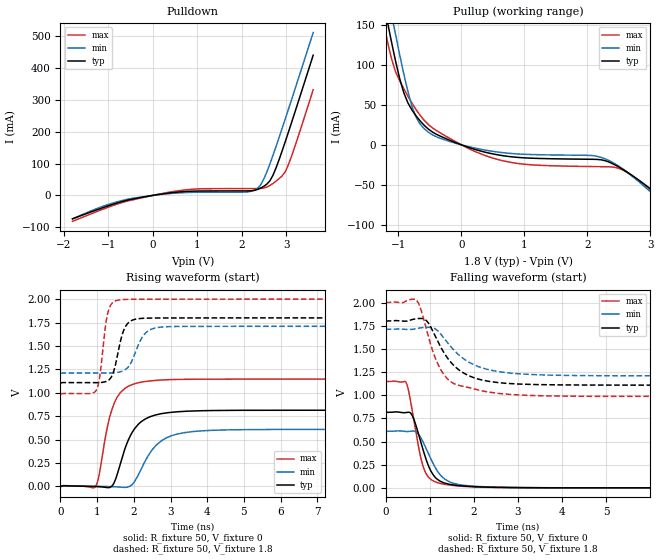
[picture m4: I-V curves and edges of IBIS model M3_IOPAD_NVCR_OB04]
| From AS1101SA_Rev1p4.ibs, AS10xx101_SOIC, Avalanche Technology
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[Model] M3_IOPAD_NVCR_OB04
Model_type Output
Enable   Active-High
Vmeas =  0.9
Cref  =  30e-12
| Capacitance  typ   min   max
C_comp   0   0   0
| Variables   typ   min   max
[GND Clamp Reference]   0   0   0
[POWER Clamp Reference]   1.8   1.71   2
[Pulldown Reference]   0   0   0
[Pullup Reference]   1.8   1.71   2
[Temperature Range]   25   105   -40
[Voltage Range]   1.8   1.71   2
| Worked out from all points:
|   slope of the pulldown table from 0 to 0.27 V, typ, clamps not added: 46.6 ohm
|   slope of the pullup table from 0 to 0.27 V, typ, clamps not added: 38.6 ohm
|   falling waveform, R_fixture 50, V_fixture 0: 20-80 % time 347ps typ, 419ps min, 280ps max; typ from 0.814 V to 0 V
|   falling waveform, R_fixture 50, V_fixture 1.8: 20-80 % time 649ps typ, 769ps min, 500ps max; typ from 1.8 V to 1.1 V
|   rising waveform, R_fixture 50, V_fixture 0: 20-80 % time 520ps typ, 636ps min, 397ps max; typ from 0 V to 0.814 V
|   rising waveform, R_fixture 50, V_fixture 1.8: 20-80 % time 256ps typ, 352ps min, 184ps max; typ from 1.1 V to 1.8 V
[Pulldown]
| Voltage   I(typ)   I(min)   I(max)
-1.8V     -73.53mA   -74.1mA    -81.36mA
-782.1mV  -23.09mA   -19.69mA   -26.48mA
310.3mV   6.56mA     4.883mA    8.631mA
993.1mV   13.72mA    9.848mA    20.32mA
2.076V    14.22mA    10.42mA    21.55mA
2.352V    18.81mA    22.19mA    21.62mA
2.49V     28.4mA     50.7mA     23.2mA
2.628V    45.71mA    98.58mA    31.1mA
2.766V    86.15mA    153.3mA    44.72mA
2.972V    168.6mA    240.1mA    74.33mA
3.179V    257.1mA    329mA      149.7mA
3.6V      441mA      512.1mA    332.5mA
[Pullup]
| Voltage   I(typ)   I(min)   I(max)
-1.8V     421.2mA    457.5mA    393mA
-1.238V   181.2mA    217.5mA    154.6mA
-1.173V   154.7mA    190.5mA    130mA
-1.108V   129.1mA    164mA      108.2mA
-1.043V   104.9mA    138mA      91.61mA
-912.4mV  65.24mA    88.85mA    70.32mA
-716.9mV  36.16mA    34.41mA    44.04mA
-456.2mV  15.91mA    12.39mA    21.19mA
682.8mV   -13.91mA   -10.07mA   -20.42mA
2.214V    -18.73mA   -15.65mA   -27.42mA
2.697V    -37.66mA   -38.46mA   -38.2mA
3.6V      -96.52mA   -101.9mA   -99.3mA
[Ramp]
dV/dt_r   0.488568/0.519945n  0.365787/0.635811n  0.687926/0.397312n
dV/dt_f   0.417076/0.649039n  0.300973/0.768787n  0.608145/0.500349n
R_load = 50
[Falling Waveform]
R_fixture = 50
V_fixture = 0
V_fixture_min = 0
V_fixture_max = 0
| Time   V(typ)   V(min)   V(max)
0s        814.3mV    609.6mV    1.147V
474.1ps   813.8mV    607.7mV    1.125V
599.7ps   783.2mV    612.6mV    837.3mV
776.9ps   525.9mV    556.8mV    365.8mV
948.2ps   264.1mV    391.6mV    129.1mV
1.058ns   153.3mV    278.2mV    80.21mV
1.23ns    73.11mV    143.7mV    48.66mV
1.546ns   30.54mV    48.34mV    24.51mV
3.663ns   898uV      1.414mV    777.2uV
21.88ns   242.1nV    617.1nV    249.8nV
[Falling Waveform]
R_fixture = 50
V_fixture = 1.8
V_fixture_min = 1.71
V_fixture_max = 2
| Time   V(typ)   V(min)   V(max)
0s        1.8V       1.71V      2V
684.9ps   1.824V     1.718V     2.031V
791.9ps   1.828V     1.727V     1.935V
954.3ps   1.787V     1.732V     1.656V
1.128ns   1.633V     1.714V     1.397V
1.355ns   1.433V     1.596V     1.2V
1.831ns   1.222V     1.372V     1.089V
2.549ns   1.136V     1.255V     1.02V
4.579ns   1.109V     1.211V     987.9mV
21.88ns   1.105V     1.208V     986.4mV
[Rising Waveform]
R_fixture = 50
V_fixture = 0
V_fixture_min = 0
V_fixture_max = 0
| Time   V(typ)   V(min)   V(max)
0s        74.44nV    376.1nV    131.9nV
944.2ps   468.1uV    1.945mV    -6.144mV
1.049ns   -1.961mV   1.585mV    113mV
1.314ns   -12.28mV   -657.4uV   697.4mV
1.509ns   84.57mV    -3.643mV   925.6mV
1.949ns   574.2mV    19.61mV    1.087V
2.418ns   740.7mV    345.5mV    1.126V
3.037ns   792.2mV    543.4mV    1.141V
4.152ns   810.9mV    599.7mV    1.146V
21.88ns   814.3mV    609.6mV    1.147V
[Rising Waveform]
R_fixture = 50
V_fixture = 1.8
V_fixture_min = 1.71
V_fixture_max = 2
| Time   V(typ)   V(min)   V(max)
0s        1.105V     1.208V     986.4mV
973.3ps   1.108V     1.21V      1.024V
1.065ns   1.109V     1.21V      1.158V
1.296ns   1.131V     1.21V      1.861V
1.443ns   1.219V     1.212V     1.968V
1.614ns   1.514V     1.223V     1.992V
1.902ns   1.764V     1.306V     1.998V
2.276ns   1.796V     1.619V     1.999V
2.814ns   1.799V     1.704V     1.999V
21.88ns   1.8V       1.71V      2V
